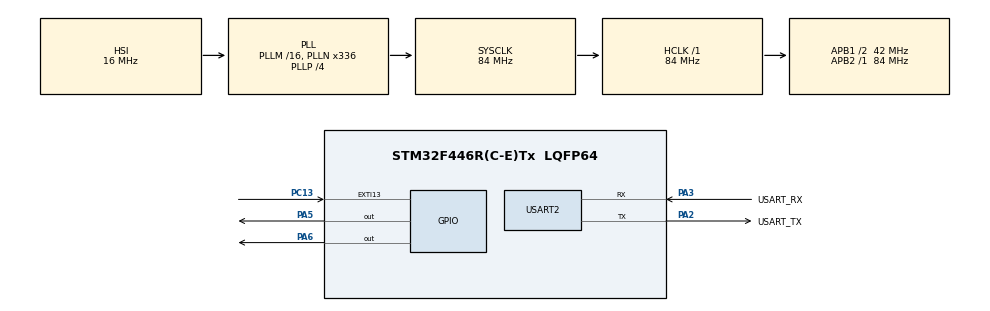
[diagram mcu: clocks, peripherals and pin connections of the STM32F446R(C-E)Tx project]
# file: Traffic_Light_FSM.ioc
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Mcu.Family=STM32F4
Mcu.Name=STM32F446R(C-E)Tx
Mcu.Package=LQFP64
NUCLEO-F446RE.BUTTON=1
NUCLEO-F446RE.Bsp_Common_DEMO=true
NUCLEO-F446RE.LD1=true
NVIC.EXTI15_10_IRQn=true\:0\:0\:false\:false\:true\:false\:true\:true
NVIC.PriorityGroup=NVIC_PRIORITYGROUP_0
NVIC.USART2_IRQn=true\:0\:0\:false\:false\:true\:true\:true\:true
PA13.GPIO_Label=TMS
PA13.Signal=SYS_JTMS-SWDIO
PA14.GPIO_Label=TCK
PA14.Signal=SYS_JTCK-SWCLK
PA2.GPIO_Label=USART_TX
PA2.Mode=Asynchronous
PA2.Signal=USART2_TX
PA3.GPIO_Label=USART_RX
PA3.Mode=Asynchronous
PA3.Signal=USART2_RX
PA5.Signal=GPIO_Output
PA6.Signal=GPIO_Output
PB3.GPIO_Label=SWO
PB3.Signal=SYS_JTDO-SWO
PC13.Signal=GPXTI13
PC14-OSC32_IN.Signal=RCC_OSC32_IN
PC15-OSC32_OUT.Signal=RCC_OSC32_OUT
PH0-OSC_IN.Signal=RCC_OSC_IN
PH1-OSC_OUT.Signal=RCC_OSC_OUT
ProjectManager.HeapSize=0x200
ProjectManager.StackSize=0x400
ProjectManager.TargetToolchain=CMake
RCC.AHBFreq_Value=84000000
RCC.APB1CLKDivider=RCC_HCLK_DIV2
RCC.APB1Freq_Value=42000000
RCC.APB1TimFreq_Value=84000000
RCC.APB2Freq_Value=84000000
RCC.APB2TimFreq_Value=84000000
RCC.CortexFreq_Value=84000000
RCC.FLatency-AdvancedSettings=FLASH_LATENCY_2
RCC.HCLKFreq_Value=84000000
RCC.HSE_VALUE=8000000
RCC.HSI_VALUE=16000000
RCC.LSE_VALUE=32768
RCC.PLLN=336
RCC.PLLP=RCC_PLLP_DIV4
RCC.SYSCLKFreq_VALUE=84000000
RCC.SYSCLKSource=RCC_SYSCLKSOURCE_PLLCLK
RCC.USBFreq_Value=168000000
RCC.VCOOutputFreq_Value=336000000
USART2.VirtualMode=VM_ASYNC
VP_NUCLEO-F446RE_VS_BSP_COMMON.Mode=COMMON
board=NUCLEO-F446RE

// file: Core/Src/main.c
/* USER CODE BEGIN Header */
/**
  ******************************************************************************
  * @file           : main.c
  * @brief          : Week 8 — Traffic light FSM (Nucleo-F446RE)
  ******************************************************************************
  */
/* USER CODE END Header */
#include "main.h"
#include "tl_fsm.h"
#include <stdio.h>
#include <string.h>

UART_HandleTypeDef huart2;
static tl_lamps_t lamps;
static tl_fsm_t fsm;
static tl_state_t last_logged;

void SystemClock_Config(void);
static void MX_GPIO_Init(void);
static void MX_USART2_UART_Init(void);

static void uart_print(const char *s)
{
  HAL_UART_Transmit(&huart2, (uint8_t *)s, (uint16_t)strlen(s), 100);
}

int main(void)
{
  const tl_timing_t timing = {
    .green_ms = 5000,
    .yellow_ms = 2000,
    .red_ms = 4000,
    .ped_ms = 5000,
    .all_red_ms = 1000
  };
  char line[48];

  HAL_Init();
  SystemClock_Config();
  MX_GPIO_Init();
  MX_USART2_UART_Init();

  lamps.red.port = GPIOA;    lamps.red.pin = GPIO_PIN_6;
  lamps.yellow.port = GPIOA; lamps.yellow.pin = GPIO_PIN_7;
  lamps.green.port = GPIOB;  lamps.green.pin = GPIO_PIN_6;
  lamps.ped.port = GPIOB;    lamps.ped.pin = GPIO_PIN_10;
  lamps.ped_present = true;

  tl_fsm_init(&fsm, &lamps, &timing);
  last_logged = tl_fsm_state(&fsm);
  uart_print("Week8 Traffic Light FSM ready — press USER for pedestrian\r\n");

  while (1)
  {
    bool ped = (HAL_GPIO_ReadPin(GPIOC, GPIO_PIN_13) == GPIO_PIN_RESET);
    tl_fsm_update(&fsm, HAL_GetTick(), ped);

    if (tl_fsm_state(&fsm) != last_logged) {
      last_logged = tl_fsm_state(&fsm);
      snprintf(line, sizeof(line), "state -> %s\r\n", tl_fsm_state_name(last_logged));
      uart_print(line);
    }
  }
}

void SystemClock_Config(void)
{
  RCC_OscInitTypeDef RCC_OscInitStruct = {0};
  RCC_ClkInitTypeDef RCC_ClkInitStruct = {0};

  __HAL_RCC_PWR_CLK_ENABLE();
  __HAL_PWR_VOLTAGESCALING_CONFIG(PWR_REGULATOR_VOLTAGE_SCALE3);

  RCC_OscInitStruct.OscillatorType = RCC_OSCILLATORTYPE_HSI;
  RCC_OscInitStruct.HSIState = RCC_HSI_ON;
  RCC_OscInitStruct.HSICalibrationValue = RCC_HSICALIBRATION_DEFAULT;
  RCC_OscInitStruct.PLL.PLLState = RCC_PLL_ON;
  RCC_OscInitStruct.PLL.PLLSource = RCC_PLLSOURCE_HSI;
  RCC_OscInitStruct.PLL.PLLM = 16;
  RCC_OscInitStruct.PLL.PLLN = 336;
  RCC_OscInitStruct.PLL.PLLP = RCC_PLLP_DIV4;
  RCC_OscInitStruct.PLL.PLLQ = 2;
  RCC_OscInitStruct.PLL.PLLR = 2;
  if (HAL_RCC_OscConfig(&RCC_OscInitStruct) != HAL_OK) {
    Error_Handler();
  }

  RCC_ClkInitStruct.ClockType = RCC_CLOCKTYPE_HCLK | RCC_CLOCKTYPE_SYSCLK
                              | RCC_CLOCKTYPE_PCLK1 | RCC_CLOCKTYPE_PCLK2;
  RCC_ClkInitStruct.SYSCLKSource = RCC_SYSCLKSOURCE_PLLCLK;
  RCC_ClkInitStruct.AHBCLKDivider = RCC_SYSCLK_DIV1;
  RCC_ClkInitStruct.APB1CLKDivider = RCC_HCLK_DIV2;
  RCC_ClkInitStruct.APB2CLKDivider = RCC_HCLK_DIV1;
  if (HAL_RCC_ClockConfig(&RCC_ClkInitStruct, FLASH_LATENCY_2) != HAL_OK) {
    Error_Handler();
  }
}

static void MX_USART2_UART_Init(void)
{
  huart2.Instance = USART2;
  huart2.Init.BaudRate = 115200;
  huart2.Init.WordLength = UART_WORDLENGTH_8B;
  huart2.Init.StopBits = UART_STOPBITS_1;
  huart2.Init.Parity = UART_PARITY_NONE;
  huart2.Init.Mode = UART_MODE_TX_RX;
  huart2.Init.HwFlowCtl = UART_HWCONTROL_NONE;
  huart2.Init.OverSampling = UART_OVERSAMPLING_16;
  if (HAL_UART_Init(&huart2) != HAL_OK) {
    Error_Handler();
  }
}

static void MX_GPIO_Init(void)
{
  GPIO_InitTypeDef GPIO_InitStruct = {0};

  __HAL_RCC_GPIOC_CLK_ENABLE();
  __HAL_RCC_GPIOH_CLK_ENABLE();
  __HAL_RCC_GPIOA_CLK_ENABLE();
  __HAL_RCC_GPIOB_CLK_ENABLE();

  HAL_GPIO_WritePin(GPIOA, GPIO_PIN_6 | GPIO_PIN_7, GPIO_PIN_RESET);
  HAL_GPIO_WritePin(GPIOB, GPIO_PIN_6 | GPIO_PIN_10, GPIO_PIN_RESET);

  /* Pedestrian / USER button PC13 EXTI */
  GPIO_InitStruct.Pin = GPIO_PIN_13;
  GPIO_InitStruct.Mode = GPIO_MODE_IT_FALLING;
  GPIO_InitStruct.Pull = GPIO_NOPULL;
  HAL_GPIO_Init(GPIOC, &GPIO_InitStruct);

  /* Red PA6, Yellow PA7 */
  GPIO_InitStruct.Pin = GPIO_PIN_6 | GPIO_PIN_7;
  GPIO_InitStruct.Mode = GPIO_MODE_OUTPUT_PP;
  GPIO_InitStruct.Pull = GPIO_NOPULL;
  GPIO_InitStruct.Speed = GPIO_SPEED_FREQ_LOW;
  HAL_GPIO_Init(GPIOA, &GPIO_InitStruct);

  /* Green PB6, Ped PB10 */
  GPIO_InitStruct.Pin = GPIO_PIN_6 | GPIO_PIN_10;
  HAL_GPIO_Init(GPIOB, &GPIO_InitStruct);

  /* USART2 */
  GPIO_InitStruct.Pin = GPIO_PIN_2 | GPIO_PIN_3;
  GPIO_InitStruct.Mode = GPIO_MODE_AF_PP;
  GPIO_InitStruct.Pull = GPIO_NOPULL;
  GPIO_InitStruct.Speed = GPIO_SPEED_FREQ_VERY_HIGH;
  GPIO_InitStruct.Alternate = GPIO_AF7_USART2;
  HAL_GPIO_Init(GPIOA, &GPIO_InitStruct);

  HAL_NVIC_SetPriority(EXTI15_10_IRQn, 0, 0);
  HAL_NVIC_EnableIRQ(EXTI15_10_IRQn);
}

void HAL_GPIO_EXTI_Callback(uint16_t GPIO_Pin)
{
  if (GPIO_Pin == GPIO_PIN_13) {
    tl_fsm_on_ped_isr(&fsm);
  }
}

void Error_Handler(void)
{
  __disable_irq();
  while (1) {
  }
}
